VERSION 5.7 ;
  NOWIREEXTENSIONATPIN ON ;
  DIVIDERCHAR "/" ;
  BUSBITCHARS "[]" ;
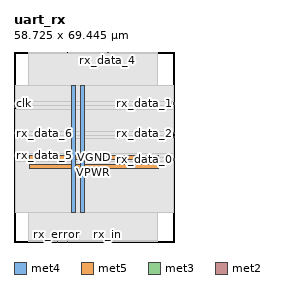
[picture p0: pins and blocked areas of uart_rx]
MACRO uart_rx
  CLASS BLOCK ;
  FOREIGN uart_rx ;
  ORIGIN 0.000 0.000 ;
  SIZE 58.725 BY 69.445 ;
  PIN VGND
    DIRECTION INOUT ;
    USE GROUND ;
    PORT
      LAYER met4 ;
        RECT 24.340 10.640 25.940 57.360 ;
    END
    PORT
      LAYER met5 ;
        RECT 5.520 30.030 52.900 31.630 ;
    END
  END VGND
  PIN VPWR
    DIRECTION INOUT ;
    USE POWER ;
    PORT
      LAYER met4 ;
        RECT 21.040 10.640 22.640 57.360 ;
    END
    PORT
      LAYER met5 ;
        RECT 5.520 26.730 52.900 28.330 ;
    END
  END VPWR
  PIN clk
    DIRECTION INPUT ;
    USE SIGNAL ;
    ANTENNAGATEAREA 1.286700 ;
    ANTENNADIFFAREA 0.434700 ;
    PORT
      LAYER met3 ;
        RECT 0.000 50.360 0.600 50.960 ;
    END
  END clk
  PIN rst_n
    DIRECTION INPUT ;
    USE SIGNAL ;
    ANTENNAGATEAREA 0.647700 ;
    ANTENNADIFFAREA 0.434700 ;
    PORT
      LAYER met3 ;
        RECT 0.000 49.000 0.600 49.600 ;
    END
  END rst_n
  PIN rx_data_0
    DIRECTION OUTPUT ;
    USE SIGNAL ;
    ANTENNAGATEAREA 0.434700 ;
    ANTENNADIFFAREA 1.137600 ;
    PORT
      LAYER met3 ;
        RECT 58.125 29.960 58.725 30.560 ;
    END
  END rx_data_0
  PIN rx_data_1
    DIRECTION OUTPUT ;
    USE SIGNAL ;
    ANTENNAGATEAREA 0.434700 ;
    ANTENNADIFFAREA 1.137600 ;
    PORT
      LAYER met3 ;
        RECT 58.125 50.360 58.725 50.960 ;
    END
  END rx_data_1
  PIN rx_data_2
    DIRECTION OUTPUT ;
    USE SIGNAL ;
    ANTENNAGATEAREA 0.434700 ;
    ANTENNADIFFAREA 1.137600 ;
    PORT
      LAYER met3 ;
        RECT 58.125 39.480 58.725 40.080 ;
    END
  END rx_data_2
  PIN rx_data_3
    DIRECTION OUTPUT ;
    USE SIGNAL ;
    ANTENNAGATEAREA 0.434700 ;
    ANTENNADIFFAREA 1.137600 ;
    PORT
      LAYER met2 ;
        RECT 19.410 69.165 19.690 69.445 ;
    END
  END rx_data_3
  PIN rx_data_4
    DIRECTION OUTPUT ;
    USE SIGNAL ;
    ANTENNAGATEAREA 0.434700 ;
    ANTENNADIFFAREA 1.137600 ;
    PORT
      LAYER met2 ;
        RECT 34.130 69.165 34.410 69.445 ;
    END
  END rx_data_4
  PIN rx_data_5
    DIRECTION OUTPUT ;
    USE SIGNAL ;
    ANTENNAGATEAREA 0.434700 ;
    ANTENNADIFFAREA 1.137600 ;
    PORT
      LAYER met3 ;
        RECT 0.000 31.320 0.600 31.920 ;
    END
  END rx_data_5
  PIN rx_data_6
    DIRECTION OUTPUT ;
    USE SIGNAL ;
    ANTENNAGATEAREA 0.434700 ;
    ANTENNADIFFAREA 1.137600 ;
    PORT
      LAYER met3 ;
        RECT 0.000 39.480 0.600 40.080 ;
    END
  END rx_data_6
  PIN rx_data_7
    DIRECTION OUTPUT ;
    USE SIGNAL ;
    ANTENNAGATEAREA 0.434700 ;
    ANTENNADIFFAREA 1.137600 ;
    PORT
      LAYER met3 ;
        RECT 58.125 38.120 58.725 38.720 ;
    END
  END rx_data_7
  PIN rx_error
    DIRECTION OUTPUT ;
    USE SIGNAL ;
    ANTENNAGATEAREA 0.434700 ;
    ANTENNADIFFAREA 1.137600 ;
    PORT
      LAYER met2 ;
        RECT 15.730 0.000 16.010 0.280 ;
    END
  END rx_error
  PIN rx_in
    DIRECTION INPUT ;
    USE SIGNAL ;
    ANTENNAGATEAREA 0.647700 ;
    ANTENNADIFFAREA 0.434700 ;
    PORT
      LAYER met2 ;
        RECT 34.130 0.000 34.410 0.280 ;
    END
  END rx_in
  PIN rx_valid
    DIRECTION OUTPUT ;
    USE SIGNAL ;
    ANTENNAGATEAREA 0.434700 ;
    ANTENNADIFFAREA 1.137600 ;
    PORT
      LAYER met2 ;
        RECT 19.410 0.000 19.690 0.280 ;
    END
  END rx_valid
  OBS
      LAYER nwell ;
        RECT 5.330 10.795 53.090 57.310 ;
      LAYER li1 ;
        RECT 5.520 10.795 52.900 57.205 ;
      LAYER met1 ;
        RECT 5.130 10.640 53.200 57.360 ;
      LAYER met2 ;
        RECT 5.150 68.885 19.130 69.165 ;
        RECT 19.970 68.885 33.850 69.165 ;
        RECT 34.690 68.885 52.350 69.165 ;
        RECT 5.150 0.560 52.350 68.885 ;
        RECT 5.150 0.280 15.450 0.560 ;
        RECT 16.290 0.280 19.130 0.560 ;
        RECT 19.970 0.280 33.850 0.560 ;
        RECT 34.690 0.280 52.350 0.560 ;
      LAYER met3 ;
        RECT 0.600 51.360 58.125 57.285 ;
        RECT 1.000 49.960 57.725 51.360 ;
        RECT 1.000 48.600 58.125 49.960 ;
        RECT 0.600 40.480 58.125 48.600 ;
        RECT 1.000 39.080 57.725 40.480 ;
        RECT 0.600 37.720 57.725 39.080 ;
        RECT 0.600 32.320 58.125 37.720 ;
        RECT 1.000 30.960 58.125 32.320 ;
        RECT 1.000 30.920 57.725 30.960 ;
        RECT 0.600 29.560 57.725 30.920 ;
        RECT 0.600 10.715 58.125 29.560 ;
  END
END uart_rx
END LIBRARY

